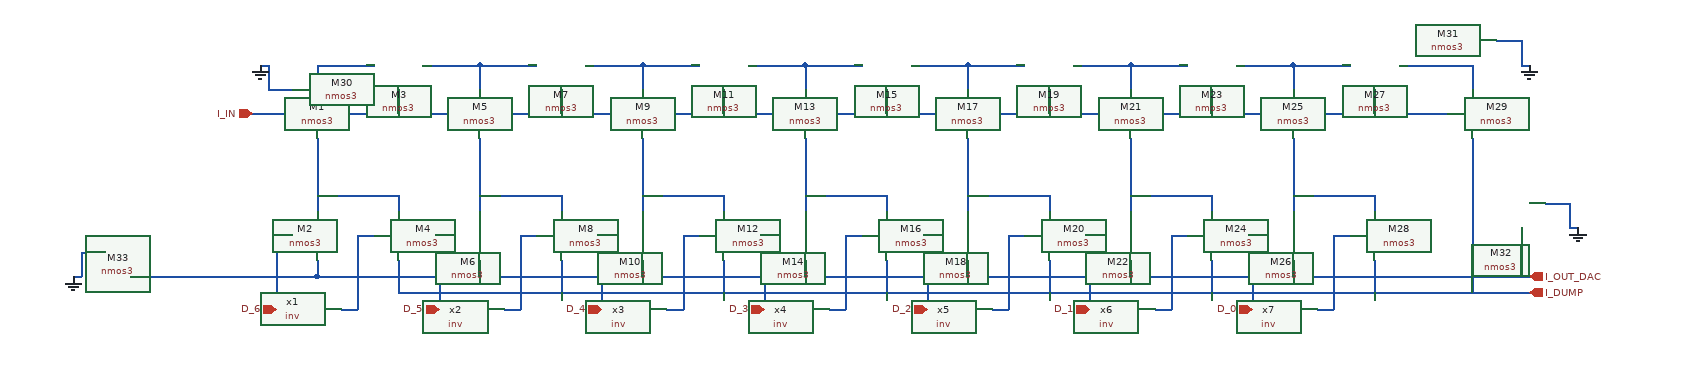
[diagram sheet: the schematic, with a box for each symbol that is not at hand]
v {xschem version=3.4.3 file_version=1.2
}
G {}
K {}
V {}
S {}
E {}
N -270 -250 -270 -220 {
lab=#net1}
N -270 -250 -200 -250 {
lab=#net1}
N -270 -160 -270 -70 {
lab=#net2}
N -170 -90 -170 -70 {
lab=#net2}
N -270 -90 -170 -90 {
lab=#net2}
N -320 -40 -300 -40 {
lab=D_6}
N -320 -40 -320 50 {
lab=D_6}
N -220 -40 -200 -40 {
lab=#net3}
N -220 -40 -220 50 {
lab=#net3}
N -70 -250 -70 -220 {
lab=#net4}
N -70 -250 0 -250 {
lab=#net4}
N -70 -160 -70 -70 {
lab=#net5}
N 30 -90 30 -70 {
lab=#net5}
N -70 -90 30 -90 {
lab=#net5}
N -120 -40 -100 -40 {
lab=D_5}
N -120 -40 -120 50 {
lab=D_5}
N -20 -40 0 -40 {
lab=#net6}
N -20 -40 -20 50 {
lab=#net6}
N 130 -250 130 -220 {
lab=#net7}
N 130 -250 200 -250 {
lab=#net7}
N 130 -160 130 -70 {
lab=#net8}
N 230 -90 230 -70 {
lab=#net8}
N 130 -90 230 -90 {
lab=#net8}
N 80 -40 100 -40 {
lab=D_4}
N 80 -40 80 50 {
lab=D_4}
N 180 -40 200 -40 {
lab=#net9}
N 180 -40 180 50 {
lab=#net9}
N 330 -250 330 -220 {
lab=#net10}
N 330 -250 400 -250 {
lab=#net10}
N 330 -160 330 -70 {
lab=#net11}
N 430 -90 430 -70 {
lab=#net11}
N 330 -90 430 -90 {
lab=#net11}
N 280 -40 300 -40 {
lab=D_3}
N 280 -40 280 50 {
lab=D_3}
N 380 -40 400 -40 {
lab=#net12}
N 380 -40 380 50 {
lab=#net12}
N 530 -250 530 -220 {
lab=#net13}
N 530 -250 600 -250 {
lab=#net13}
N 530 -160 530 -70 {
lab=#net14}
N 630 -90 630 -70 {
lab=#net14}
N 530 -90 630 -90 {
lab=#net14}
N 480 -40 500 -40 {
lab=D_2}
N 480 -40 480 50 {
lab=D_2}
N 580 -40 600 -40 {
lab=#net15}
N 580 -40 580 50 {
lab=#net15}
N 730 -250 730 -220 {
lab=#net16}
N 730 -250 800 -250 {
lab=#net16}
N 730 -160 730 -70 {
lab=#net17}
N 830 -90 830 -70 {
lab=#net17}
N 730 -90 830 -90 {
lab=#net17}
N 680 -40 700 -40 {
lab=D_1}
N 680 -40 680 50 {
lab=D_1}
N 780 -40 800 -40 {
lab=#net18}
N 780 -40 780 50 {
lab=#net18}
N 930 -250 930 -220 {
lab=#net19}
N 930 -250 1000 -250 {
lab=#net19}
N 930 -160 930 -70 {
lab=#net20}
N 1030 -90 1030 -70 {
lab=#net20}
N 930 -90 1030 -90 {
lab=#net20}
N 880 -40 900 -40 {
lab=D_0}
N 880 -40 880 50 {
lab=D_0}
N 980 -40 1000 -40 {
lab=#net21}
N 980 -40 980 50 {
lab=#net21}
N -140 -250 -70 -250 {
lab=#net4}
N 60 -250 130 -250 {
lab=#net7}
N 260 -250 330 -250 {
lab=#net10}
N 460 -250 530 -250 {
lab=#net13}
N 660 -250 730 -250 {
lab=#net16}
N 860 -250 930 -250 {
lab=#net19}
N 1060 -250 1120 -250 {
lab=#net22}
N 1120 -250 1150 -250 {
lab=#net22}
N 1150 -250 1150 -220 {
lab=#net22}
N -340 -190 -300 -190 {
lab=I_IN}
N -270 -10 -270 10 {
lab=I_OUT_DAC}
N -170 -10 -170 30 {
lab=I_DUMP}
N -70 -10 -70 10 {
lab=I_OUT_DAC}
N -270 10 1140 10 {
lab=I_OUT_DAC}
N -170 30 1140 30 {
lab=I_DUMP}
N 30 -10 30 30 {
lab=I_DUMP}
N 130 -10 130 10 {
lab=I_OUT_DAC}
N 230 -10 230 30 {
lab=I_DUMP}
N 330 -10 330 10 {
lab=I_OUT_DAC}
N 430 -10 430 30 {
lab=I_DUMP}
N 530 -10 530 10 {
lab=I_OUT_DAC}
N 630 -10 630 30 {
lab=I_DUMP}
N 730 -10 730 10 {
lab=I_OUT_DAC}
N 830 -10 830 30 {
lab=I_DUMP}
N 930 -10 930 10 {
lab=I_OUT_DAC}
N 1030 -10 1030 30 {
lab=I_DUMP}
N 1190 10 1220 10 {
lab=I_OUT_DAC}
N 1190 30 1220 30 {
lab=I_DUMP}
N -300 -190 1120 -190 {
lab=I_IN}
N 1150 -160 1150 -50 {
lab=I_DUMP}
N 1150 -50 1150 30 {
lab=I_DUMP}
N 1140 30 1180 30 {
lab=I_DUMP}
N 1140 10 1180 10 {
lab=I_OUT_DAC}
N -170 -220 -170 -190 {
lab=I_IN}
N 30 -220 30 -190 {
lab=I_IN}
N 230 -220 230 -190 {
lab=I_IN}
N 430 -220 430 -190 {
lab=I_IN}
N 630 -220 630 -190 {
lab=I_IN}
N 830 -220 830 -190 {
lab=I_IN}
N 1030 -220 1030 -190 {
lab=I_IN}
N -240 50 -220 50 {
lab=#net3}
N -40 50 -20 50 {
lab=#net6}
N 160 50 180 50 {
lab=#net9}
N 360 50 380 50 {
lab=#net12}
N 560 50 580 50 {
lab=#net15}
N 760 50 780 50 {
lab=#net18}
N 960 50 980 50 {
lab=#net21}
N 1180 -280 1210 -280 {
lab=GND}
N 1210 -280 1210 -250 {
lab=GND}
N 1210 -250 1220 -250 {
lab=GND}
N -500 10 -270 10 {
lab=I_OUT_DAC}
N 1210 -50 1210 10 {
lab=I_OUT_DAC}
N 1240 -80 1270 -80 {
lab=GND}
N 1270 -80 1270 -50 {
lab=GND}
N 1270 -50 1280 -50 {
lab=GND}
N -560 -20 -530 -20 {
lab=GND}
N -560 -20 -560 10 {
lab=GND}
N -570 10 -560 10 {
lab=GND}
N -350 -190 -340 -190 {
lab=I_IN}
N 1180 30 1190 30 {
lab=I_DUMP}
N 1180 10 1190 10 {
lab=I_OUT_DAC}
N -330 -220 -300 -220 {
lab=GND}
N -330 -250 -330 -220 {
lab=GND}
N -340 -250 -330 -250 {
lab=GND}
C {madvlsi/nmos3.sym} -270 -190 0 0 {name=M1
L=4
W=32
body=GND
nf=1
mult=1
ad="'int((nf+1)/2) * W/nf * 0.29'" 
pd="'2*int((nf+1)/2) * (W/nf + 0.29)'"
as="'int((nf+2)/2) * W/nf * 0.29'" 
ps="'2*int((nf+2)/2) * (W/nf + 0.29)'"
nrd="'0.29 / W'" nrs="'0.29 / W'"
sa=0 sb=0 sd=0
model=nfet_01v8
spiceprefix=X
}
C {madvlsi/nmos3.sym} -270 -40 0 0 {name=M2
L=4
W=32
body=GND
nf=1
mult=1
ad="'int((nf+1)/2) * W/nf * 0.29'" 
pd="'2*int((nf+1)/2) * (W/nf + 0.29)'"
as="'int((nf+2)/2) * W/nf * 0.29'" 
ps="'2*int((nf+2)/2) * (W/nf + 0.29)'"
nrd="'0.29 / W'" nrs="'0.29 / W'"
sa=0 sb=0 sd=0
model=nfet_01v8
spiceprefix=X
}
C {madvlsi/nmos3.sym} -170 -250 3 0 {name=M3
L=4
W=32
body=GND
nf=1
mult=1
ad="'int((nf+1)/2) * W/nf * 0.29'" 
pd="'2*int((nf+1)/2) * (W/nf + 0.29)'"
as="'int((nf+2)/2) * W/nf * 0.29'" 
ps="'2*int((nf+2)/2) * (W/nf + 0.29)'"
nrd="'0.29 / W'" nrs="'0.29 / W'"
sa=0 sb=0 sd=0
model=nfet_01v8
spiceprefix=X
}
C {madvlsi/nmos3.sym} -170 -40 0 0 {name=M4
L=4
W=32
body=GND
nf=1
mult=1
ad="'int((nf+1)/2) * W/nf * 0.29'" 
pd="'2*int((nf+1)/2) * (W/nf + 0.29)'"
as="'int((nf+2)/2) * W/nf * 0.29'" 
ps="'2*int((nf+2)/2) * (W/nf + 0.29)'"
nrd="'0.29 / W'" nrs="'0.29 / W'"
sa=0 sb=0 sd=0
model=nfet_01v8
spiceprefix=X
}
C {madvlsi/nmos3.sym} -70 -190 0 0 {name=M5
L=4
W=32
body=GND
nf=1
mult=1
ad="'int((nf+1)/2) * W/nf * 0.29'" 
pd="'2*int((nf+1)/2) * (W/nf + 0.29)'"
as="'int((nf+2)/2) * W/nf * 0.29'" 
ps="'2*int((nf+2)/2) * (W/nf + 0.29)'"
nrd="'0.29 / W'" nrs="'0.29 / W'"
sa=0 sb=0 sd=0
model=nfet_01v8
spiceprefix=X
}
C {madvlsi/nmos3.sym} -70 -40 0 0 {name=M6
L=4
W=32
body=GND
nf=1
mult=1
ad="'int((nf+1)/2) * W/nf * 0.29'" 
pd="'2*int((nf+1)/2) * (W/nf + 0.29)'"
as="'int((nf+2)/2) * W/nf * 0.29'" 
ps="'2*int((nf+2)/2) * (W/nf + 0.29)'"
nrd="'0.29 / W'" nrs="'0.29 / W'"
sa=0 sb=0 sd=0
model=nfet_01v8
spiceprefix=X
}
C {madvlsi/nmos3.sym} 30 -250 3 0 {name=M7
L=4
W=32
body=GND
nf=1
mult=1
ad="'int((nf+1)/2) * W/nf * 0.29'" 
pd="'2*int((nf+1)/2) * (W/nf + 0.29)'"
as="'int((nf+2)/2) * W/nf * 0.29'" 
ps="'2*int((nf+2)/2) * (W/nf + 0.29)'"
nrd="'0.29 / W'" nrs="'0.29 / W'"
sa=0 sb=0 sd=0
model=nfet_01v8
spiceprefix=X
}
C {madvlsi/nmos3.sym} 30 -40 0 0 {name=M8
L=4
W=32
body=GND
nf=1
mult=1
ad="'int((nf+1)/2) * W/nf * 0.29'" 
pd="'2*int((nf+1)/2) * (W/nf + 0.29)'"
as="'int((nf+2)/2) * W/nf * 0.29'" 
ps="'2*int((nf+2)/2) * (W/nf + 0.29)'"
nrd="'0.29 / W'" nrs="'0.29 / W'"
sa=0 sb=0 sd=0
model=nfet_01v8
spiceprefix=X
}
C {madvlsi/nmos3.sym} 130 -190 0 0 {name=M9
L=4
W=32
body=GND
nf=1
mult=1
ad="'int((nf+1)/2) * W/nf * 0.29'" 
pd="'2*int((nf+1)/2) * (W/nf + 0.29)'"
as="'int((nf+2)/2) * W/nf * 0.29'" 
ps="'2*int((nf+2)/2) * (W/nf + 0.29)'"
nrd="'0.29 / W'" nrs="'0.29 / W'"
sa=0 sb=0 sd=0
model=nfet_01v8
spiceprefix=X
}
C {madvlsi/nmos3.sym} 130 -40 0 0 {name=M10
L=4
W=32
body=GND
nf=1
mult=1
ad="'int((nf+1)/2) * W/nf * 0.29'" 
pd="'2*int((nf+1)/2) * (W/nf + 0.29)'"
as="'int((nf+2)/2) * W/nf * 0.29'" 
ps="'2*int((nf+2)/2) * (W/nf + 0.29)'"
nrd="'0.29 / W'" nrs="'0.29 / W'"
sa=0 sb=0 sd=0
model=nfet_01v8
spiceprefix=X
}
C {madvlsi/nmos3.sym} 230 -250 3 0 {name=M11
L=4
W=32
body=GND
nf=1
mult=1
ad="'int((nf+1)/2) * W/nf * 0.29'" 
pd="'2*int((nf+1)/2) * (W/nf + 0.29)'"
as="'int((nf+2)/2) * W/nf * 0.29'" 
ps="'2*int((nf+2)/2) * (W/nf + 0.29)'"
nrd="'0.29 / W'" nrs="'0.29 / W'"
sa=0 sb=0 sd=0
model=nfet_01v8
spiceprefix=X
}
C {madvlsi/nmos3.sym} 230 -40 0 0 {name=M12
L=4
W=32
body=GND
nf=1
mult=1
ad="'int((nf+1)/2) * W/nf * 0.29'" 
pd="'2*int((nf+1)/2) * (W/nf + 0.29)'"
as="'int((nf+2)/2) * W/nf * 0.29'" 
ps="'2*int((nf+2)/2) * (W/nf + 0.29)'"
nrd="'0.29 / W'" nrs="'0.29 / W'"
sa=0 sb=0 sd=0
model=nfet_01v8
spiceprefix=X
}
C {madvlsi/nmos3.sym} 330 -190 0 0 {name=M13
L=4
W=32
body=GND
nf=1
mult=1
ad="'int((nf+1)/2) * W/nf * 0.29'" 
pd="'2*int((nf+1)/2) * (W/nf + 0.29)'"
as="'int((nf+2)/2) * W/nf * 0.29'" 
ps="'2*int((nf+2)/2) * (W/nf + 0.29)'"
nrd="'0.29 / W'" nrs="'0.29 / W'"
sa=0 sb=0 sd=0
model=nfet_01v8
spiceprefix=X
}
C {madvlsi/nmos3.sym} 330 -40 0 0 {name=M14
L=4
W=32
body=GND
nf=1
mult=1
ad="'int((nf+1)/2) * W/nf * 0.29'" 
pd="'2*int((nf+1)/2) * (W/nf + 0.29)'"
as="'int((nf+2)/2) * W/nf * 0.29'" 
ps="'2*int((nf+2)/2) * (W/nf + 0.29)'"
nrd="'0.29 / W'" nrs="'0.29 / W'"
sa=0 sb=0 sd=0
model=nfet_01v8
spiceprefix=X
}
C {madvlsi/nmos3.sym} 430 -250 3 0 {name=M15
L=4
W=32
body=GND
nf=1
mult=1
ad="'int((nf+1)/2) * W/nf * 0.29'" 
pd="'2*int((nf+1)/2) * (W/nf + 0.29)'"
as="'int((nf+2)/2) * W/nf * 0.29'" 
ps="'2*int((nf+2)/2) * (W/nf + 0.29)'"
nrd="'0.29 / W'" nrs="'0.29 / W'"
sa=0 sb=0 sd=0
model=nfet_01v8
spiceprefix=X
}
C {madvlsi/nmos3.sym} 430 -40 0 0 {name=M16
L=4
W=32
body=GND
nf=1
mult=1
ad="'int((nf+1)/2) * W/nf * 0.29'" 
pd="'2*int((nf+1)/2) * (W/nf + 0.29)'"
as="'int((nf+2)/2) * W/nf * 0.29'" 
ps="'2*int((nf+2)/2) * (W/nf + 0.29)'"
nrd="'0.29 / W'" nrs="'0.29 / W'"
sa=0 sb=0 sd=0
model=nfet_01v8
spiceprefix=X
}
C {madvlsi/nmos3.sym} 530 -190 0 0 {name=M17
L=4
W=32
body=GND
nf=1
mult=1
ad="'int((nf+1)/2) * W/nf * 0.29'" 
pd="'2*int((nf+1)/2) * (W/nf + 0.29)'"
as="'int((nf+2)/2) * W/nf * 0.29'" 
ps="'2*int((nf+2)/2) * (W/nf + 0.29)'"
nrd="'0.29 / W'" nrs="'0.29 / W'"
sa=0 sb=0 sd=0
model=nfet_01v8
spiceprefix=X
}
C {madvlsi/nmos3.sym} 530 -40 0 0 {name=M18
L=4
W=32
body=GND
nf=1
mult=1
ad="'int((nf+1)/2) * W/nf * 0.29'" 
pd="'2*int((nf+1)/2) * (W/nf + 0.29)'"
as="'int((nf+2)/2) * W/nf * 0.29'" 
ps="'2*int((nf+2)/2) * (W/nf + 0.29)'"
nrd="'0.29 / W'" nrs="'0.29 / W'"
sa=0 sb=0 sd=0
model=nfet_01v8
spiceprefix=X
}
C {madvlsi/nmos3.sym} 630 -250 3 0 {name=M19
L=4
W=32
body=GND
nf=1
mult=1
ad="'int((nf+1)/2) * W/nf * 0.29'" 
pd="'2*int((nf+1)/2) * (W/nf + 0.29)'"
as="'int((nf+2)/2) * W/nf * 0.29'" 
ps="'2*int((nf+2)/2) * (W/nf + 0.29)'"
nrd="'0.29 / W'" nrs="'0.29 / W'"
sa=0 sb=0 sd=0
model=nfet_01v8
spiceprefix=X
}
C {madvlsi/nmos3.sym} 630 -40 0 0 {name=M20
L=4
W=32
body=GND
nf=1
mult=1
ad="'int((nf+1)/2) * W/nf * 0.29'" 
pd="'2*int((nf+1)/2) * (W/nf + 0.29)'"
as="'int((nf+2)/2) * W/nf * 0.29'" 
ps="'2*int((nf+2)/2) * (W/nf + 0.29)'"
nrd="'0.29 / W'" nrs="'0.29 / W'"
sa=0 sb=0 sd=0
model=nfet_01v8
spiceprefix=X
}
C {madvlsi/nmos3.sym} 730 -190 0 0 {name=M21
L=4
W=32
body=GND
nf=1
mult=1
ad="'int((nf+1)/2) * W/nf * 0.29'" 
pd="'2*int((nf+1)/2) * (W/nf + 0.29)'"
as="'int((nf+2)/2) * W/nf * 0.29'" 
ps="'2*int((nf+2)/2) * (W/nf + 0.29)'"
nrd="'0.29 / W'" nrs="'0.29 / W'"
sa=0 sb=0 sd=0
model=nfet_01v8
spiceprefix=X
}
C {madvlsi/nmos3.sym} 730 -40 0 0 {name=M22
L=4
W=32
body=GND
nf=1
mult=1
ad="'int((nf+1)/2) * W/nf * 0.29'" 
pd="'2*int((nf+1)/2) * (W/nf + 0.29)'"
as="'int((nf+2)/2) * W/nf * 0.29'" 
ps="'2*int((nf+2)/2) * (W/nf + 0.29)'"
nrd="'0.29 / W'" nrs="'0.29 / W'"
sa=0 sb=0 sd=0
model=nfet_01v8
spiceprefix=X
}
C {madvlsi/nmos3.sym} 830 -250 3 0 {name=M23
L=4
W=32
body=GND
nf=1
mult=1
ad="'int((nf+1)/2) * W/nf * 0.29'" 
pd="'2*int((nf+1)/2) * (W/nf + 0.29)'"
as="'int((nf+2)/2) * W/nf * 0.29'" 
ps="'2*int((nf+2)/2) * (W/nf + 0.29)'"
nrd="'0.29 / W'" nrs="'0.29 / W'"
sa=0 sb=0 sd=0
model=nfet_01v8
spiceprefix=X
}
C {madvlsi/nmos3.sym} 830 -40 0 0 {name=M24
L=4
W=32
body=GND
nf=1
mult=1
ad="'int((nf+1)/2) * W/nf * 0.29'" 
pd="'2*int((nf+1)/2) * (W/nf + 0.29)'"
as="'int((nf+2)/2) * W/nf * 0.29'" 
ps="'2*int((nf+2)/2) * (W/nf + 0.29)'"
nrd="'0.29 / W'" nrs="'0.29 / W'"
sa=0 sb=0 sd=0
model=nfet_01v8
spiceprefix=X
}
C {madvlsi/nmos3.sym} 930 -190 0 0 {name=M25
L=4
W=32
body=GND
nf=1
mult=1
ad="'int((nf+1)/2) * W/nf * 0.29'" 
pd="'2*int((nf+1)/2) * (W/nf + 0.29)'"
as="'int((nf+2)/2) * W/nf * 0.29'" 
ps="'2*int((nf+2)/2) * (W/nf + 0.29)'"
nrd="'0.29 / W'" nrs="'0.29 / W'"
sa=0 sb=0 sd=0
model=nfet_01v8
spiceprefix=X
}
C {madvlsi/nmos3.sym} 930 -40 0 0 {name=M26
L=4
W=32
body=GND
nf=1
mult=1
ad="'int((nf+1)/2) * W/nf * 0.29'" 
pd="'2*int((nf+1)/2) * (W/nf + 0.29)'"
as="'int((nf+2)/2) * W/nf * 0.29'" 
ps="'2*int((nf+2)/2) * (W/nf + 0.29)'"
nrd="'0.29 / W'" nrs="'0.29 / W'"
sa=0 sb=0 sd=0
model=nfet_01v8
spiceprefix=X
}
C {madvlsi/nmos3.sym} 1030 -250 3 0 {name=M27
L=4
W=32
body=GND
nf=1
mult=1
ad="'int((nf+1)/2) * W/nf * 0.29'" 
pd="'2*int((nf+1)/2) * (W/nf + 0.29)'"
as="'int((nf+2)/2) * W/nf * 0.29'" 
ps="'2*int((nf+2)/2) * (W/nf + 0.29)'"
nrd="'0.29 / W'" nrs="'0.29 / W'"
sa=0 sb=0 sd=0
model=nfet_01v8
spiceprefix=X
}
C {madvlsi/nmos3.sym} 1030 -40 0 0 {name=M28
L=4
W=32
body=GND
nf=1
mult=1
ad="'int((nf+1)/2) * W/nf * 0.29'" 
pd="'2*int((nf+1)/2) * (W/nf + 0.29)'"
as="'int((nf+2)/2) * W/nf * 0.29'" 
ps="'2*int((nf+2)/2) * (W/nf + 0.29)'"
nrd="'0.29 / W'" nrs="'0.29 / W'"
sa=0 sb=0 sd=0
model=nfet_01v8
spiceprefix=X
}
C {madvlsi/nmos3.sym} 1150 -190 0 0 {name=M29
L=\{L\}
W=\{W\}
body=GND
nf=1
mult=1
ad="'int((nf+1)/2) * W/nf * 0.29'" 
pd="'2*int((nf+1)/2) * (W/nf + 0.29)'"
as="'int((nf+2)/2) * W/nf * 0.29'" 
ps="'2*int((nf+2)/2) * (W/nf + 0.29)'"
nrd="'0.29 / W'" nrs="'0.29 / W'"
sa=0 sb=0 sd=0
model=nfet_01v8
spiceprefix=X
}
C {devices/opin.sym} 1220 10 0 0 {name=p15 lab=I_OUT_DAC}
C {devices/opin.sym} 1220 30 0 0 {name=p16 lab=I_DUMP}
C {devices/ipin.sym} -350 -190 0 0 {name=p17 lab=I_IN}
C {/home/lxbtlr/MADVLSI-MP4-DAC/schemas/inv.sym} -170 50 0 0 {name=x1}
C {/home/lxbtlr/MADVLSI-MP4-DAC/schemas/inv.sym} 30 50 0 0 {name=x2}
C {/home/lxbtlr/MADVLSI-MP4-DAC/schemas/inv.sym} 230 50 0 0 {name=x3}
C {/home/lxbtlr/MADVLSI-MP4-DAC/schemas/inv.sym} 430 50 0 0 {name=x4}
C {/home/lxbtlr/MADVLSI-MP4-DAC/schemas/inv.sym} 630 50 0 0 {name=x5}
C {/home/lxbtlr/MADVLSI-MP4-DAC/schemas/inv.sym} 830 50 0 0 {name=x6}
C {/home/lxbtlr/MADVLSI-MP4-DAC/schemas/inv.sym} 1030 50 0 0 {name=x7}
C {madvlsi/nmos3.sym} 1180 -250 3 1 {name=M31
L=4
W=32
body=GND
nf=1
mult=1
ad="'int((nf+1)/2) * W/nf * 0.29'" 
pd="'2*int((nf+1)/2) * (W/nf + 0.29)'"
as="'int((nf+2)/2) * W/nf * 0.29'" 
ps="'2*int((nf+2)/2) * (W/nf + 0.29)'"
nrd="'0.29 / W'" nrs="'0.29 / W'"
sa=0 sb=0 sd=0
model=nfet_01v8
spiceprefix=X
}
C {madvlsi/gnd.sym} 1220 -250 0 1 {name=l1 lab=GND}
C {madvlsi/nmos3.sym} 1240 -50 3 1 {name=M32
L=4
W=32
body=GND
nf=1
mult=1
ad="'int((nf+1)/2) * W/nf * 0.29'" 
pd="'2*int((nf+1)/2) * (W/nf + 0.29)'"
as="'int((nf+2)/2) * W/nf * 0.29'" 
ps="'2*int((nf+2)/2) * (W/nf + 0.29)'"
nrd="'0.29 / W'" nrs="'0.29 / W'"
sa=0 sb=0 sd=0
model=nfet_01v8
spiceprefix=X
}
C {madvlsi/gnd.sym} 1280 -50 0 1 {name=l3 lab=GND}
C {madvlsi/nmos3.sym} -530 10 1 0 {name=M33
L=4
W=32
body=GND
nf=1
mult=1
ad="'int((nf+1)/2) * W/nf * 0.29'" 
pd="'2*int((nf+1)/2) * (W/nf + 0.29)'"
as="'int((nf+2)/2) * W/nf * 0.29'" 
ps="'2*int((nf+2)/2) * (W/nf + 0.29)'"
nrd="'0.29 / W'" nrs="'0.29 / W'"
sa=0 sb=0 sd=0
model=nfet_01v8
spiceprefix=X
}
C {madvlsi/gnd.sym} -570 10 0 0 {name=l4 lab=GND}
C {devices/ipin.sym} -320 50 0 0 {name=p2 lab=D_6}
C {devices/ipin.sym} -120 50 0 0 {name=p4 lab=D_5}
C {devices/ipin.sym} 80 50 0 0 {name=p6 lab=D_4}
C {devices/ipin.sym} 280 50 0 0 {name=p8 lab=D_3}
C {devices/ipin.sym} 480 50 0 0 {name=p10 lab=D_2}
C {devices/ipin.sym} 680 50 0 0 {name=p12 lab=D_1}
C {devices/ipin.sym} 880 50 0 0 {name=p14 lab=D_0}
C {madvlsi/nmos3.sym} -300 -250 1 1 {name=M30
L=4
W=32
body=GND
nf=1
mult=1
ad="'int((nf+1)/2) * W/nf * 0.29'" 
pd="'2*int((nf+1)/2) * (W/nf + 0.29)'"
as="'int((nf+2)/2) * W/nf * 0.29'" 
ps="'2*int((nf+2)/2) * (W/nf + 0.29)'"
nrd="'0.29 / W'" nrs="'0.29 / W'"
sa=0 sb=0 sd=0
model=nfet_01v8
spiceprefix=X
}
C {madvlsi/gnd.sym} -340 -250 2 1 {name=l2 lab=GND}
